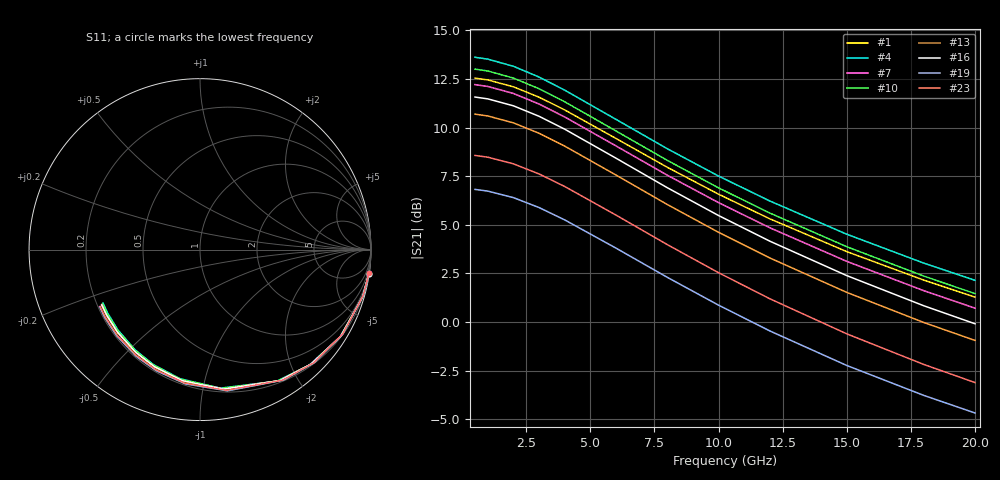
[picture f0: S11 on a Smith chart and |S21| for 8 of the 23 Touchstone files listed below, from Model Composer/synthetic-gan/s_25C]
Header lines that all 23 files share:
# Hz S RI R 50
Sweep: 500 MHz to 20 GHz
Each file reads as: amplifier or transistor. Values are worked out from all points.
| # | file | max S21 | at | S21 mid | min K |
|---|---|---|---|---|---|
| 1 | Vgs0.3_Vds2_Id53.663314.s2p | 12.5 dB | 500 MHz | 8.0 dB at 8 GHz | 0.03 |
| 2 | Vgs0.3_Vds4_Id55.357665.s2p | 13.2 dB | 500 MHz | 8.5 dB at 8 GHz | 0.02 |
| 3 | Vgs0.3_Vds7_Id57.399739.s2p | 13.4 dB | 500 MHz | 8.7 dB at 8 GHz | 0.02 |
| 4 | Vgs0.3_Vds10_Id59.231074.s2p | 13.6 dB | 500 MHz | 8.9 dB at 8 GHz | 0.02 |
| 5 | Vgs0.3_Vds15_Id61.863547.s2p | 13.9 dB | 500 MHz | 9.2 dB at 8 GHz | 0.02 |
| 6 | Vgs0_Vds1_Id32.767339.s2p | 5.0 dB | 500 MHz | 1.2 dB at 8 GHz | 0.06 |
| 7 | Vgs0_Vds2_Id37.550219.s2p | 12.2 dB | 500 MHz | 7.5 dB at 8 GHz | 0.03 |
| 8 | Vgs0_Vds4_Id38.779274.s2p | 12.5 dB | 500 MHz | 7.8 dB at 8 GHz | 0.02 |
| 9 | Vgs0_Vds7_Id40.434856.s2p | 12.8 dB | 500 MHz | 8.1 dB at 8 GHz | 0.02 |
| 10 | Vgs0_Vds10_Id41.952879.s2p | 13.0 dB | 500 MHz | 8.3 dB at 8 GHz | 0.02 |
| 11 | Vgs0_Vds15_Id44.205986.s2p | 13.3 dB | 500 MHz | 8.6 dB at 8 GHz | 0.02 |
| 12 | Vgs-0.4_Vds1_Id17.993038.s2p | 8.7 dB | 500 MHz | 4.3 dB at 8 GHz | 0.04 |
| 13 | Vgs-0.4_Vds2_Id19.113004.s2p | 10.7 dB | 500 MHz | 6.0 dB at 8 GHz | 0.03 |
| 14 | Vgs-0.4_Vds4_Id19.841504.s2p | 10.9 dB | 500 MHz | 6.3 dB at 8 GHz | 0.03 |
| 15 | Vgs-0.4_Vds7_Id20.872878.s2p | 11.3 dB | 500 MHz | 6.6 dB at 8 GHz | 0.03 |
| 16 | Vgs-0.4_Vds10_Id21.844400.s2p | 11.6 dB | 500 MHz | 6.9 dB at 8 GHz | 0.03 |
| 17 | Vgs-0.4_Vds15_Id23.340489.s2p | 12.0 dB | 500 MHz | 7.3 dB at 8 GHz | 0.02 |
| 18 | Vgs-0.8_Vds1_Id5.667405.s2p | 6.3 dB | 500 MHz | 1.8 dB at 8 GHz | 0.03 |
| 19 | Vgs-0.8_Vds2_Id5.906279.s2p | 6.8 dB | 500 MHz | 2.3 dB at 8 GHz | 0.03 |
| 20 | Vgs-0.8_Vds4_Id6.178775.s2p | 7.1 dB | 500 MHz | 2.6 dB at 8 GHz | 0.03 |
| 21 | Vgs-0.8_Vds7_Id6.575749.s2p | 7.6 dB | 500 MHz | 3.0 dB at 8 GHz | 0.03 |
| 22 | Vgs-0.8_Vds10_Id6.960280.s2p | 8.0 dB | 500 MHz | 3.4 dB at 8 GHz | 0.03 |
| 23 | Vgs-0.8_Vds15_Id7.574679.s2p | 8.6 dB | 500 MHz | 4.0 dB at 8 GHz | 0.03 |
